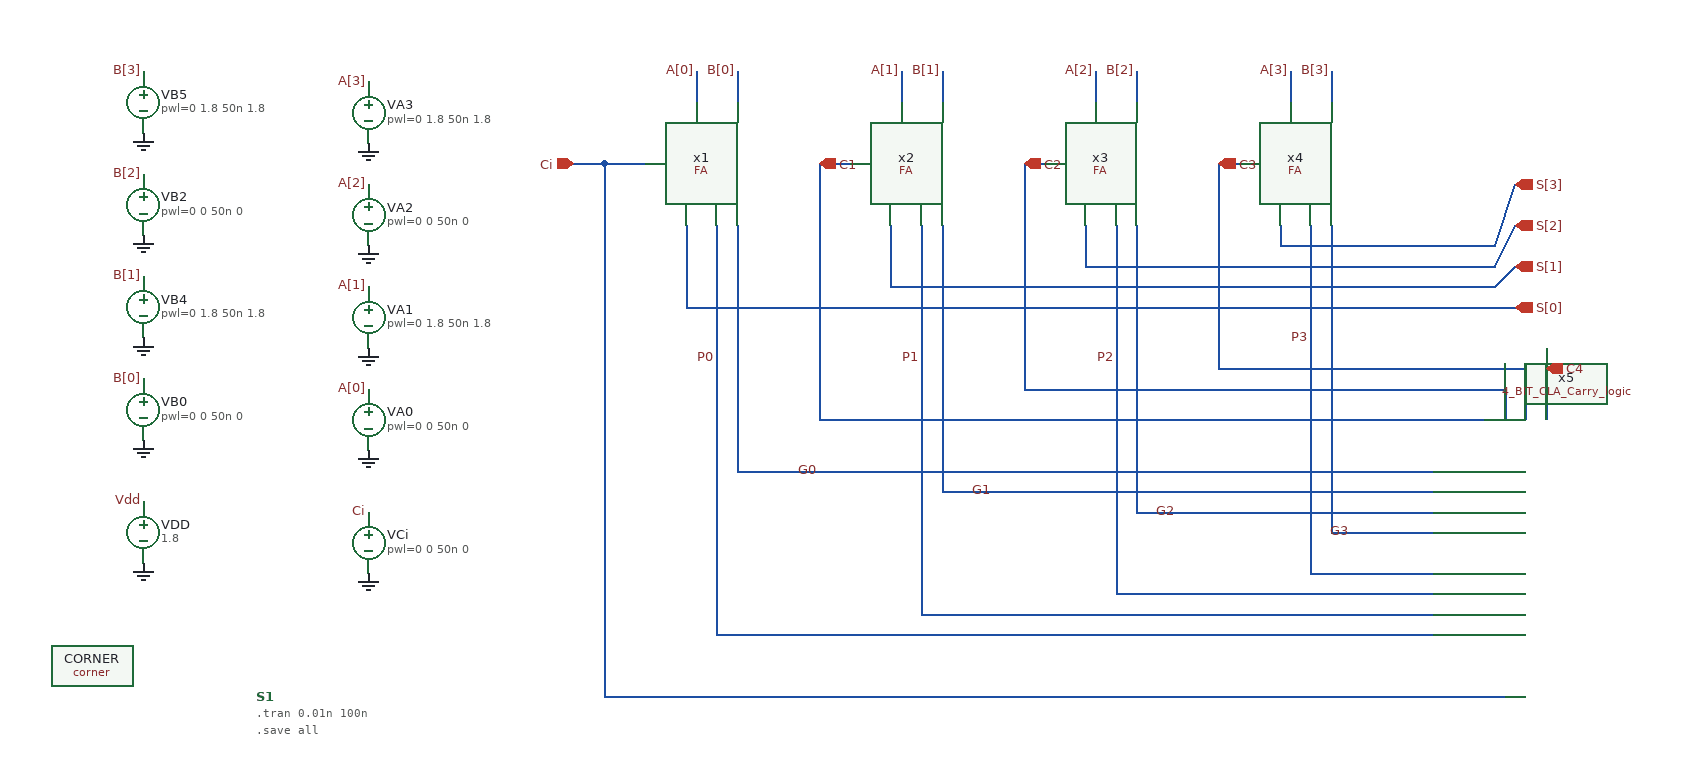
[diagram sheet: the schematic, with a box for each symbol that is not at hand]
v {xschem version=3.4.5 file_version=1.2
}
G {}
K {}
V {}
S {}
E {}
B 2 880 -2690 1680 -2290 {flags=graph
y1=0
y2=2
ypos1=-0.13781101
ypos2=1.8621889


unity=1
x1=-1e-09
x2=9e-08


xlabmag=1.0
ylabmag=1.0


dataset=-1
unitx=1
logx=0
logy=0
digital=1
rainbow=0

divx=5

subdivx=2
divy=5
subdivy=2


color="11 11 11 11 11 11"
node="a;a[3],a[2],a[1],a[0]
b;b[3],b[2],b[1],b[0]
ci;ci
p;p3,p2,p1,p0
g;g3,g2,g1,g0
sum;c4,s[3],s[2],s[1],s[0]"}
N 1060 -3280 1100 -3280 {
lab=Ci}
N 1150 -3370 1150 -3340 {
lab=#net1}
N 1190 -3370 1190 -3340 {
lab=#net2}
N 1350 -3370 1350 -3340 {
lab=#net3}
N 1390 -3370 1390 -3340 {
lab=#net4}
N 1540 -3370 1540 -3340 {
lab=#net5}
N 1580 -3370 1580 -3340 {
lab=#net6}
N 1730 -3370 1730 -3340 {
lab=#net7}
N 1770 -3370 1770 -3340 {
lab=#net8}
N 1170 -3220 1170 -3180 {
lab=P0}
N 1370 -3220 1370 -3180 {
lab=P1}
N 1060 -3280 1060 -2850 {
lab=Ci}
N 1060 -2850 1060 -2760 {
lab=Ci}
N 1480 -2760 1940 -2760 {
lab=Ci}
N 1390 -2960 1870 -2960 {
lab=G1}
N 1390 -3220 1390 -2960 {
lab=G1}
N 1580 -3220 1580 -2940 {
lab=G2}
N 1580 -2940 1870 -2940 {
lab=G2}
N 1770 -3220 1770 -2920 {
lab=G3}
N 1770 -2920 1870 -2920 {
lab=G3}
N 1060 -2760 1480 -2760 {
lab=Ci}
N 1270 -3030 1920 -3030 {
lab=C1}
N 1270 -3280 1270 -3030 {
lab=C1}
N 1940 -3060 1940 -3030 {
lab=C2}
N 1470 -3060 1940 -3060 {
lab=C2}
N 1470 -3280 1470 -3060 {
lab=C2}
N 1960 -3080 1960 -3030 {
lab=C3}
N 1660 -3080 1960 -3080 {
lab=C3}
N 1660 -3280 1660 -3080 {
lab=C3}
N 1980 -3100 1980 -3030 {
lab=C4}
N 1720 -3220 1720 -3200 {
lab=S[3]}
N 1720 -3200 1930 -3200 {
lab=S[3]}
N 1530 -3220 1530 -3180 {
lab=S[2]}
N 1340 -3220 1340 -3160 {
lab=S[1]}
N 1340 -3160 1930 -3160 {
lab=S[1]}
N 1140 -3220 1140 -3140 {
lab=S[0]}
N 1140 -3140 1930 -3140 {
lab=S[0]}
N 1530 -3180 1930 -3180 {
lab=S[2]}
N 1930 -3200 1950 -3260 {
lab=S[3]}
N 1930 -3180 1950 -3220 {
lab=S[2]}
N 1930 -3160 1950 -3180 {
lab=S[1]}
N 1930 -3140 1950 -3140 {
lab=S[0]}
N 1190 -3220 1190 -2980 {
lab=G0}
N 1190 -2980 1870 -2980 {
lab=G0}
N 1270 -3280 1300 -3280 {
lab=C1}
N 1470 -3280 1490 -3280 {
lab=C2}
N 1660 -3280 1680 -3280 {
lab=C3}
N 1030 -3280 1060 -3280 {
lab=Ci}
N 1170 -3180 1170 -2820 {
lab=P0}
N 1170 -2820 1870 -2820 {
lab=P0}
N 1370 -2840 1870 -2840 {
lab=P1}
N 1370 -3090 1370 -2840 {
lab=P1}
N 1370 -3180 1370 -3090 {
lab=P1}
N 1560 -2860 1870 -2860 {
lab=P2}
N 1560 -3090 1560 -2860 {
lab=P2}
N 1560 -3220 1560 -3090 {
lab=P2}
N 1750 -2880 1870 -2880 {
lab=P3}
N 1750 -3110 1750 -2880 {
lab=P3}
N 1750 -3220 1750 -3110 {
lab=P3}
C {FA.sym} 1170 -3280 0 0 {name=x1}
C {FA.sym} 1370 -3280 0 0 {name=x2}
C {FA.sym} 1560 -3280 0 0 {name=x3}
C {FA.sym} 1750 -3280 0 0 {name=x4}
C {4_BIT_CLA_Carry_logic.sym} 1970 -2880 3 0 {name=x5}
C {devices/bus_tap.sym} 1150 -3370 0 0 {name=l2 lab=A[0]}
C {devices/bus_tap.sym} 1350 -3370 0 0 {name=l1 lab=A[1]}
C {devices/bus_tap.sym} 1540 -3370 0 0 {name=l3 lab=A[2]}
C {devices/bus_tap.sym} 1730 -3370 0 0 {name=l4 lab=A[3]}
C {devices/bus_tap.sym} 1190 -3370 0 0 {name=l5 lab=B[0]}
C {devices/bus_tap.sym} 1390 -3370 0 0 {name=l6 lab=B[1]}
C {devices/bus_tap.sym} 1580 -3370 0 0 {name=l7 lab=B[2]}
C {devices/bus_tap.sym} 1770 -3370 0 0 {name=l8 lab=B[3]}
C {devices/opin.sym} 1950 -3260 0 0 {name=p13 lab=S[3]}
C {devices/opin.sym} 1950 -3220 0 0 {name=p10 lab=S[2]}
C {devices/opin.sym} 1950 -3180 0 0 {name=p11 lab=S[1]}
C {devices/opin.sym} 1950 -3140 0 0 {name=p12 lab=S[0]}
C {devices/vsource.sym} 830 -3330 0 0 {name=VA3 value="pwl=0 1.8 50n 1.8" savecurrent=false}
C {devices/lab_pin.sym} 830 -3360 0 0 {name=p1 sig_type=std_logic lab=A[3]}
C {devices/vsource.sym} 830 -3230 0 0 {name=VA2 value="pwl=0 0 50n 0 " savecurrent=false}
C {devices/lab_pin.sym} 830 -3260 0 0 {name=p2 sig_type=std_logic lab=A[2]}
C {devices/vsource.sym} 830 -3130 0 0 {name=VA1 value="pwl=0 1.8 50n 1.8 " savecurrent=false}
C {devices/lab_pin.sym} 830 -3160 0 0 {name=p3 sig_type=std_logic lab=A[1]}
C {devices/vsource.sym} 830 -3030 0 0 {name=VA0 value="pwl=0 0 50n 0" savecurrent=false}
C {devices/lab_pin.sym} 830 -3060 0 0 {name=VA4 sig_type=std_logic lab=A[0]}
C {devices/vsource.sym} 610 -3340 0 0 {name=VB5 value="pwl=0 1.8 50n 1.8 " savecurrent=false}
C {devices/lab_pin.sym} 610 -3370 0 0 {name=VB1 sig_type=std_logic lab=B[3]}
C {devices/vsource.sym} 610 -3240 0 0 {name=VB2 value="pwl=0 0 50n 0 " savecurrent=false}
C {devices/lab_pin.sym} 610 -3270 0 0 {name=VB3 sig_type=std_logic lab=B[2]}
C {devices/vsource.sym} 610 -3140 0 0 {name=VB4 value="pwl=0 1.8 50n 1.8 " savecurrent=false}
C {devices/lab_pin.sym} 610 -3170 0 0 {name=VB6 sig_type=std_logic lab=B[1]}
C {devices/vsource.sym} 610 -3040 0 0 {name=VB0 value="pwl=0 0 50n 0" savecurrent=false}
C {devices/lab_pin.sym} 610 -3070 0 0 {name=VB8 sig_type=std_logic lab=B[0]}
C {devices/gnd.sym} 830 -3000 0 0 {name=l13 lab=GND}
C {devices/gnd.sym} 610 -3010 0 0 {name=l14 lab=GND}
C {devices/gnd.sym} 830 -3100 0 0 {name=l15 lab=GND}
C {devices/gnd.sym} 610 -3110 0 0 {name=l16 lab=GND}
C {devices/gnd.sym} 830 -3200 0 0 {name=l17 lab=GND}
C {devices/gnd.sym} 610 -3210 0 0 {name=l18 lab=GND}
C {devices/gnd.sym} 610 -3310 0 0 {name=l19 lab=GND}
C {devices/gnd.sym} 830 -3300 0 0 {name=l20 lab=GND}
C {devices/ipin.sym} 1030 -3280 0 0 {name=p4 sig_type=std_logic lab=Ci}
C {devices/vsource.sym} 830 -2910 0 0 {name=VCi value="pwl=0 0 50n 0 " savecurrent=false}
C {devices/lab_pin.sym} 830 -2940 0 0 {name=Ci1 sig_type=std_logic lab=Ci}
C {devices/gnd.sym} 830 -2880 0 0 {name=Ci2 lab=GND}
C {devices/opin.sym} 1980 -3080 3 0 {name=p5 sig_type=std_logic lab=C4}
C {devices/launcher.sym} 970 -2230 0 0 {name=h5
descr="load waves" 
tclcommand="xschem raw_read $netlist_dir/CLA_4BIT.raw tran"
}
C {sky130_fd_pr/corner.sym} 560 -2790 0 0 {name=CORNER only_toplevel=true corner=tt}
C {devices/code_shown.sym} 720 -2760 0 0 {name=S1 only_toplevel=false value=".tran 0.01n 100n
.save all"}
C {devices/opin.sym} 1270 -3280 3 0 {name=p14 sig_type=std_logic lab=C1}
C {devices/opin.sym} 1470 -3280 3 0 {name=p15 sig_type=std_logic lab=C2}
C {devices/opin.sym} 1660 -3280 3 0 {name=p16 sig_type=std_logic lab=C3}
C {devices/vsource.sym} 610 -2920 0 0 {name=VDD value=1.8 savecurrent=false}
C {devices/lab_pin.sym} 610 -2950 0 0 {name=Ci3 sig_type=std_logic lab=Vdd}
C {devices/gnd.sym} 610 -2890 0 0 {name=Ci4 lab=GND}
C {devices/lab_pin.sym} 1170 -3090 0 0 {name=p6 sig_type=std_logic lab=P0}
C {devices/lab_pin.sym} 1270 -2980 0 0 {name=p7 sig_type=std_logic lab=G0}
C {devices/lab_pin.sym} 1440 -2960 0 0 {name=p8 sig_type=std_logic lab=G1}
C {devices/lab_pin.sym} 1620 -2940 0 0 {name=p9 sig_type=std_logic lab=G2}
C {devices/lab_pin.sym} 1790 -2920 0 0 {name=p17 sig_type=std_logic lab=G3}
C {devices/lab_pin.sym} 1370 -3090 0 0 {name=p18 sig_type=std_logic lab=P1}
C {devices/lab_pin.sym} 1560 -3090 0 0 {name=p19 sig_type=std_logic lab=P2}
C {devices/lab_pin.sym} 1750 -3110 0 0 {name=p20 sig_type=std_logic lab=P3}
